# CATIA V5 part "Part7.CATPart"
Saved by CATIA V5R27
Part number: Part2
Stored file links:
  E:\university\my-thesis\My Thesis Publication\Final-Updata\CAD\Part7.CATPart

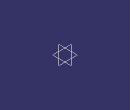
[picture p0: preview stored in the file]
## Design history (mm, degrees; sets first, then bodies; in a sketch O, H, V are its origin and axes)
Body1 (main body)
